One B-rep face of a CAD part: STEP entity #931.
In plain terms, the planar face has unit normal (0, -0.669, -0.743).
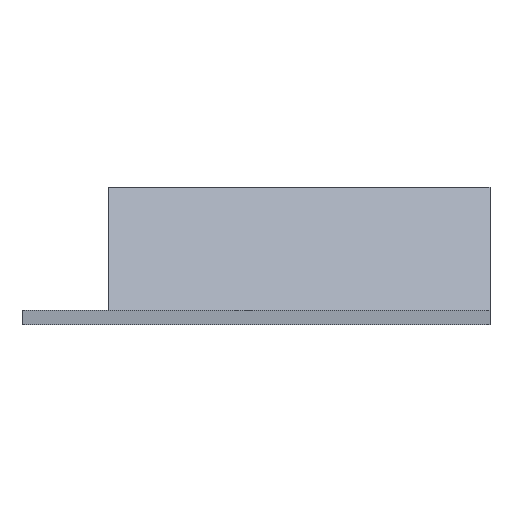
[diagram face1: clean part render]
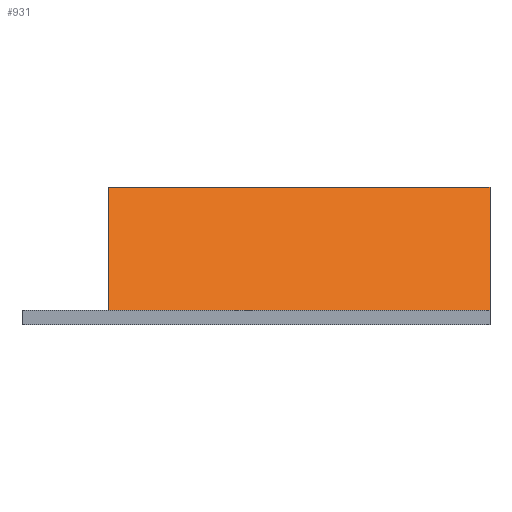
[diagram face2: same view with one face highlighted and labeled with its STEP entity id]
Its self-contained STEP definition (entity closure, numbers rounded to 3 decimals):
#118 = PLANE('',#119);
#119 = AXIS2_PLACEMENT_3D('',#120,#121,#122);
#120 = CARTESIAN_POINT('',(-40.,92.,56.));
#121 = DIRECTION('',(1.,0.,0.));
#122 = DIRECTION('',(0.,0.,1.));
#144 = PLANE('',#145);
#145 = AXIS2_PLACEMENT_3D('',#146,#147,#148);
#146 = CARTESIAN_POINT('',(-76.644,92.,83.928));
#147 = DIRECTION('',(-0.,-1.,-0.));
#148 = DIRECTION('',(0.,0.,-1.));
#316 = VERTEX_POINT('',#317);
#317 = CARTESIAN_POINT('',(-40.,72.,128.6));
#331 = PLANE('',#332);
#332 = AXIS2_PLACEMENT_3D('',#333,#334,#335);
#333 = CARTESIAN_POINT('',(-40.,72.,132.));
#334 = DIRECTION('',(0.,1.,0.));
#335 = DIRECTION('',(-1.,0.,0.));
#343 = EDGE_CURVE('',#344,#316,#346,.T.);
#344 = VERTEX_POINT('',#345);
#345 = CARTESIAN_POINT('',(-40.,92.,110.6));
#346 = SURFACE_CURVE('',#347,(#351,#358),.PCURVE_S1.);
#347 = LINE('',#348,#349);
#348 = CARTESIAN_POINT('',(-40.,92.,110.6));
#349 = VECTOR('',#350,1.);
#350 = DIRECTION('',(0.,-0.743,0.669));
#351 = PCURVE('',#118,#352);
#352 = DEFINITIONAL_REPRESENTATION('',(#353),#357);
#353 = LINE('',#354,#355);
#354 = CARTESIAN_POINT('',(54.6,0.));
#355 = VECTOR('',#356,1.);
#356 = DIRECTION('',(0.669,0.743));
#357 = ( GEOMETRIC_REPRESENTATION_CONTEXT(2) 
PARAMETRIC_REPRESENTATION_CONTEXT() REPRESENTATION_CONTEXT('2D SPACE',''
  ) );
#358 = PCURVE('',#359,#364);
#359 = PLANE('',#360);
#360 = AXIS2_PLACEMENT_3D('',#361,#362,#363);
#361 = CARTESIAN_POINT('',(-71.,82.,119.6));
#362 = DIRECTION('',(-0.,-0.669,-0.743));
#363 = DIRECTION('',(0.,-0.743,0.669));
#364 = DEFINITIONAL_REPRESENTATION('',(#365),#369);
#365 = LINE('',#366,#367);
#366 = CARTESIAN_POINT('',(-13.454,-31.));
#367 = VECTOR('',#368,1.);
#368 = DIRECTION('',(1.,0.));
#369 = ( GEOMETRIC_REPRESENTATION_CONTEXT(2) 
PARAMETRIC_REPRESENTATION_CONTEXT() REPRESENTATION_CONTEXT('2D SPACE',''
  ) );
#398 = EDGE_CURVE('',#399,#344,#401,.T.);
#399 = VERTEX_POINT('',#400);
#400 = CARTESIAN_POINT('',(-102.,92.,110.6));
#401 = SURFACE_CURVE('',#402,(#406,#413),.PCURVE_S1.);
#402 = LINE('',#403,#404);
#403 = CARTESIAN_POINT('',(-102.,92.,110.6));
#404 = VECTOR('',#405,1.);
#405 = DIRECTION('',(1.,0.,0.));
#406 = PCURVE('',#144,#407);
#407 = DEFINITIONAL_REPRESENTATION('',(#408),#412);
#408 = LINE('',#409,#410);
#409 = CARTESIAN_POINT('',(-26.672,-25.356));
#410 = VECTOR('',#411,1.);
#411 = DIRECTION('',(0.,1.));
#412 = ( GEOMETRIC_REPRESENTATION_CONTEXT(2) 
PARAMETRIC_REPRESENTATION_CONTEXT() REPRESENTATION_CONTEXT('2D SPACE',''
  ) );
#413 = PCURVE('',#359,#414);
#414 = DEFINITIONAL_REPRESENTATION('',(#415),#419);
#415 = LINE('',#416,#417);
#416 = CARTESIAN_POINT('',(-13.454,31.));
#417 = VECTOR('',#418,1.);
#418 = DIRECTION('',(0.,-1.));
#419 = ( GEOMETRIC_REPRESENTATION_CONTEXT(2) 
PARAMETRIC_REPRESENTATION_CONTEXT() REPRESENTATION_CONTEXT('2D SPACE',''
  ) );
#437 = PLANE('',#438);
#438 = AXIS2_PLACEMENT_3D('',#439,#440,#441);
#439 = CARTESIAN_POINT('',(-102.,72.,132.));
#440 = DIRECTION('',(1.,0.,0.));
#441 = DIRECTION('',(0.,0.743,-0.669));
#887 = EDGE_CURVE('',#316,#888,#890,.T.);
#888 = VERTEX_POINT('',#889);
#889 = CARTESIAN_POINT('',(-102.,72.,128.6));
#890 = SURFACE_CURVE('',#891,(#895,#902),.PCURVE_S1.);
#891 = LINE('',#892,#893);
#892 = CARTESIAN_POINT('',(-40.,72.,128.6));
#893 = VECTOR('',#894,1.);
#894 = DIRECTION('',(-1.,0.,0.));
#895 = PCURVE('',#331,#896);
#896 = DEFINITIONAL_REPRESENTATION('',(#897),#901);
#897 = LINE('',#898,#899);
#898 = CARTESIAN_POINT('',(0.,-3.4));
#899 = VECTOR('',#900,1.);
#900 = DIRECTION('',(1.,0.));
#901 = ( GEOMETRIC_REPRESENTATION_CONTEXT(2) 
PARAMETRIC_REPRESENTATION_CONTEXT() REPRESENTATION_CONTEXT('2D SPACE',''
  ) );
#902 = PCURVE('',#359,#903);
#903 = DEFINITIONAL_REPRESENTATION('',(#904),#908);
#904 = LINE('',#905,#906);
#905 = CARTESIAN_POINT('',(13.454,-31.));
#906 = VECTOR('',#907,1.);
#907 = DIRECTION('',(0.,1.));
#908 = ( GEOMETRIC_REPRESENTATION_CONTEXT(2) 
PARAMETRIC_REPRESENTATION_CONTEXT() REPRESENTATION_CONTEXT('2D SPACE',''
  ) );
#931 = ADVANCED_FACE('',(#932),#359,.T.);
#932 = FACE_BOUND('',#933,.T.);
#933 = EDGE_LOOP('',(#934,#935,#936,#937));
#934 = ORIENTED_EDGE('',*,*,#398,.T.);
#935 = ORIENTED_EDGE('',*,*,#343,.T.);
#936 = ORIENTED_EDGE('',*,*,#887,.T.);
#937 = ORIENTED_EDGE('',*,*,#938,.T.);
#938 = EDGE_CURVE('',#888,#399,#939,.T.);
#939 = SURFACE_CURVE('',#940,(#944,#951),.PCURVE_S1.);
#940 = LINE('',#941,#942);
#941 = CARTESIAN_POINT('',(-102.,72.,128.6));
#942 = VECTOR('',#943,1.);
#943 = DIRECTION('',(0.,0.743,-0.669));
#944 = PCURVE('',#359,#945);
#945 = DEFINITIONAL_REPRESENTATION('',(#946),#950);
#946 = LINE('',#947,#948);
#947 = CARTESIAN_POINT('',(13.454,31.));
#948 = VECTOR('',#949,1.);
#949 = DIRECTION('',(-1.,0.));
#950 = ( GEOMETRIC_REPRESENTATION_CONTEXT(2) 
PARAMETRIC_REPRESENTATION_CONTEXT() REPRESENTATION_CONTEXT('2D SPACE',''
  ) );
#951 = PCURVE('',#437,#952);
#952 = DEFINITIONAL_REPRESENTATION('',(#953),#957);
#953 = LINE('',#954,#955);
#954 = CARTESIAN_POINT('',(2.274,-2.527));
#955 = VECTOR('',#956,1.);
#956 = DIRECTION('',(1.,0.));
#957 = ( GEOMETRIC_REPRESENTATION_CONTEXT(2) 
PARAMETRIC_REPRESENTATION_CONTEXT() REPRESENTATION_CONTEXT('2D SPACE',''
  ) );
